VERSION 5.8 ;
BUSBITCHARS "[]" ;

UNITS
  DATABASE MICRONS 1000 ;
END UNITS

PROPERTYDEFINITIONS
  MACRO expanded_util REAL ;
END PROPERTYDEFINITIONS

LAYER OVERLAP
  TYPE OVERLAP ;
END OVERLAP

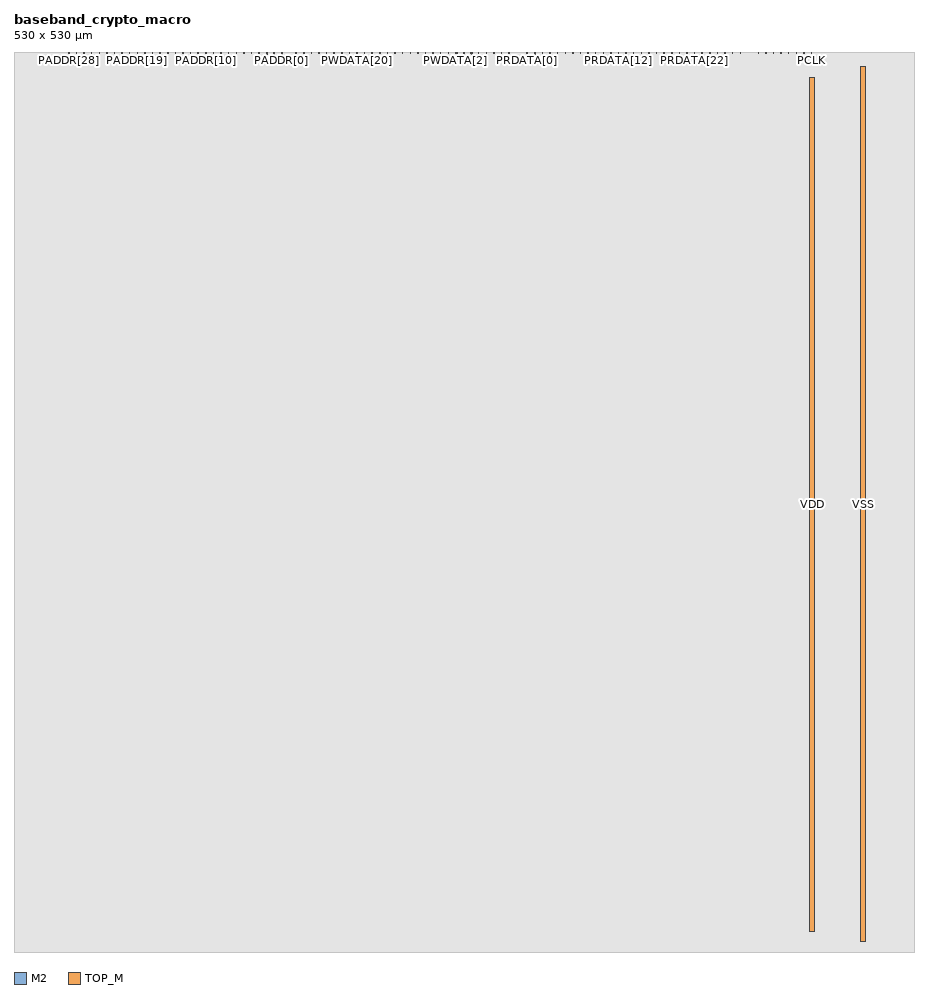
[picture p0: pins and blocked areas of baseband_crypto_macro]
MACRO baseband_crypto_macro
  CLASS BLOCK ;
  ORIGIN 0 0 ;
  SIZE 530 BY 530 ;
  SYMMETRY X Y ;
  PIN PCLK
    DIRECTION INPUT ;
    USE CLOCK ;
    PORT
      LAYER M2 ;
        RECT 469.54 529.275 469.82 530 ;
    END
  END PCLK
  PIN PRESETn
    DIRECTION INPUT ;
    USE SIGNAL ;
    PORT
      LAYER M2 ;
        RECT 465.06 529.275 465.34 530 ;
    END
  END PRESETn
  PIN PSEL
    DIRECTION INPUT ;
    USE SIGNAL ;
    PORT
      LAYER M2 ;
        RECT 460.58 529.275 460.86 530 ;
    END
  END PSEL
  PIN PENABLE
    DIRECTION INPUT ;
    USE SIGNAL ;
    PORT
      LAYER M2 ;
        RECT 456.1 529.275 456.38 530 ;
    END
  END PENABLE
  PIN PWRITE
    DIRECTION INPUT ;
    USE SIGNAL ;
    PORT
      LAYER M2 ;
        RECT 451.62 529.275 451.9 530 ;
    END
  END PWRITE
  PIN PADDR[31]
    DIRECTION INPUT ;
    USE SIGNAL ;
    PORT
      LAYER TOP_M ;
        RECT 148.58 528.72 149.02 530 ;
    END
  END PADDR[31]
  PIN PADDR[30]
    DIRECTION INPUT ;
    USE SIGNAL ;
    PORT
      LAYER TOP_M ;
        RECT 153.06 528.72 153.5 530 ;
    END
  END PADDR[30]
  PIN PADDR[29]
    DIRECTION INPUT ;
    USE SIGNAL ;
    PORT
      LAYER TOP_M ;
        RECT 157.54 528.72 157.98 530 ;
    END
  END PADDR[29]
  PIN PADDR[28]
    DIRECTION INPUT ;
    USE SIGNAL ;
    PORT
      LAYER M2 ;
        RECT 32.18 529.275 32.46 530 ;
    END
  END PADDR[28]
  PIN PADDR[27]
    DIRECTION INPUT ;
    USE SIGNAL ;
    PORT
      LAYER M2 ;
        RECT 36.66 529.275 36.94 530 ;
    END
  END PADDR[27]
  PIN PADDR[26]
    DIRECTION INPUT ;
    USE SIGNAL ;
    PORT
      LAYER M2 ;
        RECT 41.14 529.275 41.42 530 ;
    END
  END PADDR[26]
  PIN PADDR[25]
    DIRECTION INPUT ;
    USE SIGNAL ;
    PORT
      LAYER M2 ;
        RECT 45.62 529.275 45.9 530 ;
    END
  END PADDR[25]
  PIN PADDR[24]
    DIRECTION INPUT ;
    USE SIGNAL ;
    PORT
      LAYER M2 ;
        RECT 50.1 529.275 50.38 530 ;
    END
  END PADDR[24]
  PIN PADDR[23]
    DIRECTION INPUT ;
    USE SIGNAL ;
    PORT
      LAYER M2 ;
        RECT 54.58 529.275 54.86 530 ;
    END
  END PADDR[23]
  PIN PADDR[22]
    DIRECTION INPUT ;
    USE SIGNAL ;
    PORT
      LAYER M2 ;
        RECT 59.06 529.275 59.34 530 ;
    END
  END PADDR[22]
  PIN PADDR[21]
    DIRECTION INPUT ;
    USE SIGNAL ;
    PORT
      LAYER M2 ;
        RECT 63.54 529.275 63.82 530 ;
    END
  END PADDR[21]
  PIN PADDR[20]
    DIRECTION INPUT ;
    USE SIGNAL ;
    PORT
      LAYER M2 ;
        RECT 68.02 529.275 68.3 530 ;
    END
  END PADDR[20]
  PIN PADDR[19]
    DIRECTION INPUT ;
    USE SIGNAL ;
    PORT
      LAYER M2 ;
        RECT 72.5 529.275 72.78 530 ;
    END
  END PADDR[19]
  PIN PADDR[18]
    DIRECTION INPUT ;
    USE SIGNAL ;
    PORT
      LAYER M2 ;
        RECT 76.98 529.275 77.26 530 ;
    END
  END PADDR[18]
  PIN PADDR[17]
    DIRECTION INPUT ;
    USE SIGNAL ;
    PORT
      LAYER M2 ;
        RECT 81.46 529.275 81.74 530 ;
    END
  END PADDR[17]
  PIN PADDR[16]
    DIRECTION INPUT ;
    USE SIGNAL ;
    PORT
      LAYER M2 ;
        RECT 85.94 529.275 86.22 530 ;
    END
  END PADDR[16]
  PIN PADDR[15]
    DIRECTION INPUT ;
    USE SIGNAL ;
    PORT
      LAYER M2 ;
        RECT 90.42 529.275 90.7 530 ;
    END
  END PADDR[15]
  PIN PADDR[14]
    DIRECTION INPUT ;
    USE SIGNAL ;
    PORT
      LAYER M2 ;
        RECT 94.9 529.275 95.18 530 ;
    END
  END PADDR[14]
  PIN PADDR[13]
    DIRECTION INPUT ;
    USE SIGNAL ;
    PORT
      LAYER M2 ;
        RECT 99.38 529.275 99.66 530 ;
    END
  END PADDR[13]
  PIN PADDR[12]
    DIRECTION INPUT ;
    USE SIGNAL ;
    PORT
      LAYER M2 ;
        RECT 103.86 529.275 104.14 530 ;
    END
  END PADDR[12]
  PIN PADDR[11]
    DIRECTION INPUT ;
    USE SIGNAL ;
    PORT
      LAYER M2 ;
        RECT 108.34 529.275 108.62 530 ;
    END
  END PADDR[11]
  PIN PADDR[10]
    DIRECTION INPUT ;
    USE SIGNAL ;
    PORT
      LAYER M2 ;
        RECT 112.82 529.275 113.1 530 ;
    END
  END PADDR[10]
  PIN PADDR[9]
    DIRECTION INPUT ;
    USE SIGNAL ;
    PORT
      LAYER M2 ;
        RECT 117.3 529.275 117.58 530 ;
    END
  END PADDR[9]
  PIN PADDR[8]
    DIRECTION INPUT ;
    USE SIGNAL ;
    PORT
      LAYER M2 ;
        RECT 121.78 529.275 122.06 530 ;
    END
  END PADDR[8]
  PIN PADDR[7]
    DIRECTION INPUT ;
    USE SIGNAL ;
    PORT
      LAYER M2 ;
        RECT 126.26 529.275 126.54 530 ;
    END
  END PADDR[7]
  PIN PADDR[6]
    DIRECTION INPUT ;
    USE SIGNAL ;
    PORT
      LAYER M2 ;
        RECT 130.74 529.275 131.02 530 ;
    END
  END PADDR[6]
  PIN PADDR[5]
    DIRECTION INPUT ;
    USE SIGNAL ;
    PORT
      LAYER M2 ;
        RECT 135.22 529.275 135.5 530 ;
    END
  END PADDR[5]
  PIN PADDR[4]
    DIRECTION INPUT ;
    USE SIGNAL ;
    PORT
      LAYER M2 ;
        RECT 139.7 529.275 139.98 530 ;
    END
  END PADDR[4]
  PIN PADDR[3]
    DIRECTION INPUT ;
    USE SIGNAL ;
    PORT
      LAYER M2 ;
        RECT 144.18 529.275 144.46 530 ;
    END
  END PADDR[3]
  PIN PADDR[2]
    DIRECTION INPUT ;
    USE SIGNAL ;
    PORT
      LAYER M2 ;
        RECT 148.66 529.275 148.94 530 ;
    END
  END PADDR[2]
  PIN PADDR[1]
    DIRECTION INPUT ;
    USE SIGNAL ;
    PORT
      LAYER M2 ;
        RECT 153.14 529.275 153.42 530 ;
    END
  END PADDR[1]
  PIN PADDR[0]
    DIRECTION INPUT ;
    USE SIGNAL ;
    PORT
      LAYER M2 ;
        RECT 157.62 529.275 157.9 530 ;
    END
  END PADDR[0]
  PIN PWDATA[31]
    DIRECTION INPUT ;
    USE SIGNAL ;
    PORT
      LAYER TOP_M ;
        RECT 269.54 528.72 269.98 530 ;
    END
  END PWDATA[31]
  PIN PWDATA[30]
    DIRECTION INPUT ;
    USE SIGNAL ;
    PORT
      LAYER TOP_M ;
        RECT 260.58 528.72 261.02 530 ;
    END
  END PWDATA[30]
  PIN PWDATA[29]
    DIRECTION INPUT ;
    USE SIGNAL ;
    PORT
      LAYER TOP_M ;
        RECT 265.06 528.72 265.5 530 ;
    END
  END PWDATA[29]
  PIN PWDATA[28]
    DIRECTION INPUT ;
    USE SIGNAL ;
    PORT
      LAYER M2 ;
        RECT 166.02 529.275 166.3 530 ;
    END
  END PWDATA[28]
  PIN PWDATA[27]
    DIRECTION INPUT ;
    USE SIGNAL ;
    PORT
      LAYER M2 ;
        RECT 170.5 529.275 170.78 530 ;
    END
  END PWDATA[27]
  PIN PWDATA[26]
    DIRECTION INPUT ;
    USE SIGNAL ;
    PORT
      LAYER M2 ;
        RECT 174.98 529.275 175.26 530 ;
    END
  END PWDATA[26]
  PIN PWDATA[25]
    DIRECTION INPUT ;
    USE SIGNAL ;
    PORT
      LAYER M2 ;
        RECT 179.46 529.275 179.74 530 ;
    END
  END PWDATA[25]
  PIN PWDATA[24]
    DIRECTION INPUT ;
    USE SIGNAL ;
    PORT
      LAYER M2 ;
        RECT 183.94 529.275 184.22 530 ;
    END
  END PWDATA[24]
  PIN PWDATA[23]
    DIRECTION INPUT ;
    USE SIGNAL ;
    PORT
      LAYER M2 ;
        RECT 188.42 529.275 188.7 530 ;
    END
  END PWDATA[23]
  PIN PWDATA[22]
    DIRECTION INPUT ;
    USE SIGNAL ;
    PORT
      LAYER M2 ;
        RECT 192.9 529.275 193.18 530 ;
    END
  END PWDATA[22]
  PIN PWDATA[21]
    DIRECTION INPUT ;
    USE SIGNAL ;
    PORT
      LAYER M2 ;
        RECT 197.38 529.275 197.66 530 ;
    END
  END PWDATA[21]
  PIN PWDATA[20]
    DIRECTION INPUT ;
    USE SIGNAL ;
    PORT
      LAYER M2 ;
        RECT 201.86 529.275 202.14 530 ;
    END
  END PWDATA[20]
  PIN PWDATA[19]
    DIRECTION INPUT ;
    USE SIGNAL ;
    PORT
      LAYER M2 ;
        RECT 206.34 529.275 206.62 530 ;
    END
  END PWDATA[19]
  PIN PWDATA[18]
    DIRECTION INPUT ;
    USE SIGNAL ;
    PORT
      LAYER M2 ;
        RECT 210.82 529.275 211.1 530 ;
    END
  END PWDATA[18]
  PIN PWDATA[17]
    DIRECTION INPUT ;
    USE SIGNAL ;
    PORT
      LAYER M2 ;
        RECT 215.3 529.275 215.58 530 ;
    END
  END PWDATA[17]
  PIN PWDATA[16]
    DIRECTION INPUT ;
    USE SIGNAL ;
    PORT
      LAYER M2 ;
        RECT 219.78 529.275 220.06 530 ;
    END
  END PWDATA[16]
  PIN PWDATA[15]
    DIRECTION INPUT ;
    USE SIGNAL ;
    PORT
      LAYER M2 ;
        RECT 224.26 529.275 224.54 530 ;
    END
  END PWDATA[15]
  PIN PWDATA[14]
    DIRECTION INPUT ;
    USE SIGNAL ;
    PORT
      LAYER M2 ;
        RECT 228.74 529.275 229.02 530 ;
    END
  END PWDATA[14]
  PIN PWDATA[13]
    DIRECTION INPUT ;
    USE SIGNAL ;
    PORT
      LAYER M2 ;
        RECT 233.22 529.275 233.5 530 ;
    END
  END PWDATA[13]
  PIN PWDATA[12]
    DIRECTION INPUT ;
    USE SIGNAL ;
    PORT
      LAYER M2 ;
        RECT 237.7 529.275 237.98 530 ;
    END
  END PWDATA[12]
  PIN PWDATA[11]
    DIRECTION INPUT ;
    USE SIGNAL ;
    PORT
      LAYER M2 ;
        RECT 291.46 529.275 291.74 530 ;
    END
  END PWDATA[11]
  PIN PWDATA[10]
    DIRECTION INPUT ;
    USE SIGNAL ;
    PORT
      LAYER M2 ;
        RECT 242.18 529.275 242.46 530 ;
    END
  END PWDATA[10]
  PIN PWDATA[9]
    DIRECTION INPUT ;
    USE SIGNAL ;
    PORT
      LAYER M2 ;
        RECT 286.98 529.275 287.26 530 ;
    END
  END PWDATA[9]
  PIN PWDATA[8]
    DIRECTION INPUT ;
    USE SIGNAL ;
    PORT
      LAYER M2 ;
        RECT 246.66 529.275 246.94 530 ;
    END
  END PWDATA[8]
  PIN PWDATA[7]
    DIRECTION INPUT ;
    USE SIGNAL ;
    PORT
      LAYER M2 ;
        RECT 282.5 529.275 282.78 530 ;
    END
  END PWDATA[7]
  PIN PWDATA[6]
    DIRECTION INPUT ;
    USE SIGNAL ;
    PORT
      LAYER M2 ;
        RECT 251.14 529.275 251.42 530 ;
    END
  END PWDATA[6]
  PIN PWDATA[5]
    DIRECTION INPUT ;
    USE SIGNAL ;
    PORT
      LAYER M2 ;
        RECT 278.02 529.275 278.3 530 ;
    END
  END PWDATA[5]
  PIN PWDATA[4]
    DIRECTION INPUT ;
    USE SIGNAL ;
    PORT
      LAYER M2 ;
        RECT 255.62 529.275 255.9 530 ;
    END
  END PWDATA[4]
  PIN PWDATA[3]
    DIRECTION INPUT ;
    USE SIGNAL ;
    PORT
      LAYER M2 ;
        RECT 273.54 529.275 273.82 530 ;
    END
  END PWDATA[3]
  PIN PWDATA[2]
    DIRECTION INPUT ;
    USE SIGNAL ;
    PORT
      LAYER M2 ;
        RECT 260.1 529.275 260.38 530 ;
    END
  END PWDATA[2]
  PIN PWDATA[1]
    DIRECTION INPUT ;
    USE SIGNAL ;
    PORT
      LAYER M2 ;
        RECT 269.06 529.275 269.34 530 ;
    END
  END PWDATA[1]
  PIN PWDATA[0]
    DIRECTION INPUT ;
    USE SIGNAL ;
    PORT
      LAYER M2 ;
        RECT 264.58 529.275 264.86 530 ;
    END
  END PWDATA[0]
  PIN PRDATA[31]
    DIRECTION OUTPUT ;
    USE SIGNAL ;
    PORT
      LAYER TOP_M ;
        RECT 310.98 528.72 311.42 530 ;
    END
  END PRDATA[31]
  PIN PRDATA[30]
    DIRECTION OUTPUT ;
    USE SIGNAL ;
    PORT
      LAYER TOP_M ;
        RECT 306.5 528.72 306.94 530 ;
    END
  END PRDATA[30]
  PIN PRDATA[29]
    DIRECTION OUTPUT ;
    USE SIGNAL ;
    PORT
      LAYER TOP_M ;
        RECT 302.02 528.72 302.46 530 ;
    END
  END PRDATA[29]
  PIN PRDATA[28]
    DIRECTION OUTPUT ;
    USE SIGNAL ;
    PORT
      LAYER M2 ;
        RECT 427.54 529.275 427.82 530 ;
    END
  END PRDATA[28]
  PIN PRDATA[27]
    DIRECTION OUTPUT ;
    USE SIGNAL ;
    PORT
      LAYER M2 ;
        RECT 423.06 529.275 423.34 530 ;
    END
  END PRDATA[27]
  PIN PRDATA[26]
    DIRECTION OUTPUT ;
    USE SIGNAL ;
    PORT
      LAYER M2 ;
        RECT 418.58 529.275 418.86 530 ;
    END
  END PRDATA[26]
  PIN PRDATA[25]
    DIRECTION OUTPUT ;
    USE SIGNAL ;
    PORT
      LAYER M2 ;
        RECT 414.1 529.275 414.38 530 ;
    END
  END PRDATA[25]
  PIN PRDATA[24]
    DIRECTION OUTPUT ;
    USE SIGNAL ;
    PORT
      LAYER M2 ;
        RECT 409.62 529.275 409.9 530 ;
    END
  END PRDATA[24]
  PIN PRDATA[23]
    DIRECTION OUTPUT ;
    USE SIGNAL ;
    PORT
      LAYER M2 ;
        RECT 405.14 529.275 405.42 530 ;
    END
  END PRDATA[23]
  PIN PRDATA[22]
    DIRECTION OUTPUT ;
    USE SIGNAL ;
    PORT
      LAYER M2 ;
        RECT 400.66 529.275 400.94 530 ;
    END
  END PRDATA[22]
  PIN PRDATA[21]
    DIRECTION OUTPUT ;
    USE SIGNAL ;
    PORT
      LAYER M2 ;
        RECT 396.18 529.275 396.46 530 ;
    END
  END PRDATA[21]
  PIN PRDATA[20]
    DIRECTION OUTPUT ;
    USE SIGNAL ;
    PORT
      LAYER M2 ;
        RECT 391.7 529.275 391.98 530 ;
    END
  END PRDATA[20]
  PIN PRDATA[19]
    DIRECTION OUTPUT ;
    USE SIGNAL ;
    PORT
      LAYER M2 ;
        RECT 387.22 529.275 387.5 530 ;
    END
  END PRDATA[19]
  PIN PRDATA[18]
    DIRECTION OUTPUT ;
    USE SIGNAL ;
    PORT
      LAYER M2 ;
        RECT 382.74 529.275 383.02 530 ;
    END
  END PRDATA[18]
  PIN PRDATA[17]
    DIRECTION OUTPUT ;
    USE SIGNAL ;
    PORT
      LAYER M2 ;
        RECT 378.26 529.275 378.54 530 ;
    END
  END PRDATA[17]
  PIN PRDATA[16]
    DIRECTION OUTPUT ;
    USE SIGNAL ;
    PORT
      LAYER M2 ;
        RECT 373.78 529.275 374.06 530 ;
    END
  END PRDATA[16]
  PIN PRDATA[15]
    DIRECTION OUTPUT ;
    USE SIGNAL ;
    PORT
      LAYER M2 ;
        RECT 369.3 529.275 369.58 530 ;
    END
  END PRDATA[15]
  PIN PRDATA[14]
    DIRECTION OUTPUT ;
    USE SIGNAL ;
    PORT
      LAYER M2 ;
        RECT 364.82 529.275 365.1 530 ;
    END
  END PRDATA[14]
  PIN PRDATA[13]
    DIRECTION OUTPUT ;
    USE SIGNAL ;
    PORT
      LAYER M2 ;
        RECT 360.34 529.275 360.62 530 ;
    END
  END PRDATA[13]
  PIN PRDATA[12]
    DIRECTION OUTPUT ;
    USE SIGNAL ;
    PORT
      LAYER M2 ;
        RECT 355.86 529.275 356.14 530 ;
    END
  END PRDATA[12]
  PIN PRDATA[11]
    DIRECTION OUTPUT ;
    USE SIGNAL ;
    PORT
      LAYER M2 ;
        RECT 351.38 529.275 351.66 530 ;
    END
  END PRDATA[11]
  PIN PRDATA[10]
    DIRECTION OUTPUT ;
    USE SIGNAL ;
    PORT
      LAYER M2 ;
        RECT 346.9 529.275 347.18 530 ;
    END
  END PRDATA[10]
  PIN PRDATA[9]
    DIRECTION OUTPUT ;
    USE SIGNAL ;
    PORT
      LAYER M2 ;
        RECT 342.42 529.275 342.7 530 ;
    END
  END PRDATA[9]
  PIN PRDATA[8]
    DIRECTION OUTPUT ;
    USE SIGNAL ;
    PORT
      LAYER M2 ;
        RECT 337.94 529.275 338.22 530 ;
    END
  END PRDATA[8]
  PIN PRDATA[7]
    DIRECTION OUTPUT ;
    USE SIGNAL ;
    PORT
      LAYER M2 ;
        RECT 333.46 529.275 333.74 530 ;
    END
  END PRDATA[7]
  PIN PRDATA[6]
    DIRECTION OUTPUT ;
    USE SIGNAL ;
    PORT
      LAYER M2 ;
        RECT 328.98 529.275 329.26 530 ;
    END
  END PRDATA[6]
  PIN PRDATA[5]
    DIRECTION OUTPUT ;
    USE SIGNAL ;
    PORT
      LAYER M2 ;
        RECT 324.5 529.275 324.78 530 ;
    END
  END PRDATA[5]
  PIN PRDATA[4]
    DIRECTION OUTPUT ;
    USE SIGNAL ;
    PORT
      LAYER M2 ;
        RECT 320.02 529.275 320.3 530 ;
    END
  END PRDATA[4]
  PIN PRDATA[3]
    DIRECTION OUTPUT ;
    USE SIGNAL ;
    PORT
      LAYER M2 ;
        RECT 315.54 529.275 315.82 530 ;
    END
  END PRDATA[3]
  PIN PRDATA[2]
    DIRECTION OUTPUT ;
    USE SIGNAL ;
    PORT
      LAYER M2 ;
        RECT 311.06 529.275 311.34 530 ;
    END
  END PRDATA[2]
  PIN PRDATA[1]
    DIRECTION OUTPUT ;
    USE SIGNAL ;
    PORT
      LAYER M2 ;
        RECT 306.58 529.275 306.86 530 ;
    END
  END PRDATA[1]
  PIN PRDATA[0]
    DIRECTION OUTPUT ;
    USE SIGNAL ;
    PORT
      LAYER M2 ;
        RECT 302.1 529.275 302.38 530 ;
    END
  END PRDATA[0]
  PIN PREADY
    DIRECTION OUTPUT ;
    USE SIGNAL ;
    PORT
      LAYER M2 ;
        RECT 447.14 529.275 447.42 530 ;
    END
  END PREADY
  PIN rfid_rx_bit
    DIRECTION INPUT ;
    USE SIGNAL ;
    PORT
      LAYER M2 ;
        RECT 442.66 529.275 442.94 530 ;
    END
  END rfid_rx_bit
  PIN rfid_tx_bit
    DIRECTION OUTPUT ;
    USE SIGNAL ;
    PORT
      LAYER M2 ;
        RECT 438.18 529.275 438.46 530 ;
    END
  END rfid_tx_bit
  PIN VDD
    DIRECTION INPUT ;
    USE POWER ;
    PORT
      LAYER TOP_M ;
        RECT 468.75 12 471.25 515.2 ;
    END
  END VDD
  PIN VSS
    DIRECTION INPUT ;
    USE GROUND ;
    PORT
      LAYER TOP_M ;
        RECT 498.75 6 501.25 521.2 ;
    END
  END VSS
  OBS
    LAYER GC SPACING 0 ;
      RECT 0 0 530 530 ;
    LAYER M1 SPACING 0 ;
      RECT 0 0 530 530 ;
    LAYER M2 SPACING 0 ;
      RECT 264.86 529.275 269.06 530 ;
      RECT 0 0 530 529.275 ;
      RECT 396.46 529.275 400.66 530 ;
      RECT 400.94 529.275 405.14 530 ;
      RECT 405.42 529.275 409.62 530 ;
      RECT 409.9 529.275 414.1 530 ;
      RECT 414.38 529.275 418.58 530 ;
      RECT 418.86 529.275 423.06 530 ;
      RECT 423.34 529.275 427.54 530 ;
      RECT 427.82 529.275 438.18 530 ;
      RECT 438.46 529.275 442.66 530 ;
      RECT 442.94 529.275 447.14 530 ;
      RECT 447.42 529.275 451.62 530 ;
      RECT 451.9 529.275 456.1 530 ;
      RECT 456.38 529.275 460.58 530 ;
      RECT 460.86 529.275 465.06 530 ;
      RECT 465.34 529.275 469.54 530 ;
      RECT 469.82 529.275 530 530 ;
      RECT 329.26 529.275 333.46 530 ;
      RECT 333.74 529.275 337.94 530 ;
      RECT 338.22 529.275 342.42 530 ;
      RECT 342.7 529.275 346.9 530 ;
      RECT 347.18 529.275 351.38 530 ;
      RECT 351.66 529.275 355.86 530 ;
      RECT 356.14 529.275 360.34 530 ;
      RECT 360.62 529.275 364.82 530 ;
      RECT 365.1 529.275 369.3 530 ;
      RECT 369.58 529.275 373.78 530 ;
      RECT 374.06 529.275 378.26 530 ;
      RECT 378.54 529.275 382.74 530 ;
      RECT 383.02 529.275 387.22 530 ;
      RECT 387.5 529.275 391.7 530 ;
      RECT 391.98 529.275 396.18 530 ;
      RECT 269.34 529.275 273.54 530 ;
      RECT 273.82 529.275 278.02 530 ;
      RECT 278.3 529.275 282.5 530 ;
      RECT 282.78 529.275 286.98 530 ;
      RECT 287.26 529.275 291.46 530 ;
      RECT 291.74 529.275 302.1 530 ;
      RECT 302.38 529.275 306.58 530 ;
      RECT 306.86 529.275 311.06 530 ;
      RECT 311.34 529.275 315.54 530 ;
      RECT 315.82 529.275 320.02 530 ;
      RECT 320.3 529.275 324.5 530 ;
      RECT 324.78 529.275 328.98 530 ;
      RECT 131.02 529.275 135.22 530 ;
      RECT 197.66 529.275 201.86 530 ;
      RECT 202.14 529.275 206.34 530 ;
      RECT 206.62 529.275 210.82 530 ;
      RECT 211.1 529.275 215.3 530 ;
      RECT 215.58 529.275 219.78 530 ;
      RECT 220.06 529.275 224.26 530 ;
      RECT 224.54 529.275 228.74 530 ;
      RECT 229.02 529.275 233.22 530 ;
      RECT 233.5 529.275 237.7 530 ;
      RECT 237.98 529.275 242.18 530 ;
      RECT 242.46 529.275 246.66 530 ;
      RECT 246.94 529.275 251.14 530 ;
      RECT 251.42 529.275 255.62 530 ;
      RECT 255.9 529.275 260.1 530 ;
      RECT 260.38 529.275 264.58 530 ;
      RECT 135.5 529.275 139.7 530 ;
      RECT 139.98 529.275 144.18 530 ;
      RECT 144.46 529.275 148.66 530 ;
      RECT 148.94 529.275 153.14 530 ;
      RECT 153.42 529.275 157.62 530 ;
      RECT 157.9 529.275 166.02 530 ;
      RECT 166.3 529.275 170.5 530 ;
      RECT 170.78 529.275 174.98 530 ;
      RECT 175.26 529.275 179.46 530 ;
      RECT 179.74 529.275 183.94 530 ;
      RECT 184.22 529.275 188.42 530 ;
      RECT 188.7 529.275 192.9 530 ;
      RECT 193.18 529.275 197.38 530 ;
      RECT 63.82 529.275 68.02 530 ;
      RECT 68.3 529.275 72.5 530 ;
      RECT 72.78 529.275 76.98 530 ;
      RECT 77.26 529.275 81.46 530 ;
      RECT 81.74 529.275 85.94 530 ;
      RECT 86.22 529.275 90.42 530 ;
      RECT 90.7 529.275 94.9 530 ;
      RECT 95.18 529.275 99.38 530 ;
      RECT 99.66 529.275 103.86 530 ;
      RECT 104.14 529.275 108.34 530 ;
      RECT 108.62 529.275 112.82 530 ;
      RECT 113.1 529.275 117.3 530 ;
      RECT 117.58 529.275 121.78 530 ;
      RECT 122.06 529.275 126.26 530 ;
      RECT 126.54 529.275 130.74 530 ;
      RECT 0 529.275 32.18 530 ;
      RECT 32.46 529.275 36.66 530 ;
      RECT 36.94 529.275 41.14 530 ;
      RECT 41.42 529.275 45.62 530 ;
      RECT 45.9 529.275 50.1 530 ;
      RECT 50.38 529.275 54.58 530 ;
      RECT 54.86 529.275 59.06 530 ;
      RECT 59.34 529.275 63.54 530 ;
    LAYER M3 SPACING 0 ;
      RECT 0 0 530 530 ;
    LAYER TOP_M SPACING 0 ;
      RECT 0 528.72 148.58 530 ;
      RECT 149.02 528.72 153.06 530 ;
      RECT 153.5 528.72 157.54 530 ;
      RECT 157.98 528.72 260.58 530 ;
      RECT 261.02 528.72 265.06 530 ;
      RECT 265.5 528.72 269.54 530 ;
      RECT 269.98 528.72 302.02 530 ;
      RECT 302.46 528.72 306.5 530 ;
      RECT 306.94 528.72 310.98 530 ;
      RECT 311.42 528.72 530 530 ;
      RECT 0 521.2 530 528.72 ;
      RECT 0 515.2 498.75 521.2 ;
      RECT 0 12 468.75 515.2 ;
      RECT 471.25 12 498.75 515.2 ;
      RECT 501.25 6 530 521.2 ;
      RECT 0 6 498.75 12 ;
      RECT 0 0 530 6 ;
    LAYER WN SPACING 0 ;
      RECT 0 0 530 530 ;
    LAYER XP SPACING 0 ;
      RECT 0 0 530 530 ;
    LAYER XN SPACING 0 ;
      RECT 0 0 530 530 ;
    LAYER M2 ;
      RECT 0.28 0.28 529.72 528.995 ;
      RECT 396.74 528.995 400.38 529.72 ;
      RECT 401.22 528.995 404.86 529.72 ;
      RECT 405.7 528.995 409.34 529.72 ;
      RECT 410.18 528.995 413.82 529.72 ;
      RECT 414.66 528.995 418.3 529.72 ;
      RECT 419.14 528.995 422.78 529.72 ;
      RECT 423.62 528.995 427.26 529.72 ;
      RECT 428.1 528.995 437.9 529.72 ;
      RECT 438.74 528.995 442.38 529.72 ;
      RECT 443.22 528.995 446.86 529.72 ;
      RECT 447.7 528.995 451.34 529.72 ;
      RECT 452.18 528.995 455.82 529.72 ;
      RECT 456.66 528.995 460.3 529.72 ;
      RECT 461.14 528.995 464.78 529.72 ;
      RECT 465.62 528.995 469.26 529.72 ;
      RECT 470.1 528.995 529.72 529.72 ;
      RECT 329.54 528.995 333.18 529.72 ;
      RECT 334.02 528.995 337.66 529.72 ;
      RECT 338.5 528.995 342.14 529.72 ;
      RECT 342.98 528.995 346.62 529.72 ;
      RECT 347.46 528.995 351.1 529.72 ;
      RECT 351.94 528.995 355.58 529.72 ;
      RECT 356.42 528.995 360.06 529.72 ;
      RECT 360.9 528.995 364.54 529.72 ;
      RECT 365.38 528.995 369.02 529.72 ;
      RECT 369.86 528.995 373.5 529.72 ;
      RECT 374.34 528.995 377.98 529.72 ;
      RECT 378.82 528.995 382.46 529.72 ;
      RECT 383.3 528.995 386.94 529.72 ;
      RECT 387.78 528.995 391.42 529.72 ;
      RECT 392.26 528.995 395.9 529.72 ;
      RECT 265.14 528.995 268.78 529.72 ;
      RECT 269.62 528.995 273.26 529.72 ;
      RECT 274.1 528.995 277.74 529.72 ;
      RECT 278.58 528.995 282.22 529.72 ;
      RECT 283.06 528.995 286.7 529.72 ;
      RECT 287.54 528.995 291.18 529.72 ;
      RECT 292.02 528.995 301.82 529.72 ;
      RECT 302.66 528.995 306.3 529.72 ;
      RECT 307.14 528.995 310.78 529.72 ;
      RECT 311.62 528.995 315.26 529.72 ;
      RECT 316.1 528.995 319.74 529.72 ;
      RECT 320.58 528.995 324.22 529.72 ;
      RECT 325.06 528.995 328.7 529.72 ;
      RECT 131.3 528.995 134.94 529.72 ;
      RECT 197.94 528.995 201.58 529.72 ;
      RECT 202.42 528.995 206.06 529.72 ;
      RECT 206.9 528.995 210.54 529.72 ;
      RECT 211.38 528.995 215.02 529.72 ;
      RECT 215.86 528.995 219.5 529.72 ;
      RECT 220.34 528.995 223.98 529.72 ;
      RECT 224.82 528.995 228.46 529.72 ;
      RECT 229.3 528.995 232.94 529.72 ;
      RECT 233.78 528.995 237.42 529.72 ;
      RECT 238.26 528.995 241.9 529.72 ;
      RECT 242.74 528.995 246.38 529.72 ;
      RECT 247.22 528.995 250.86 529.72 ;
      RECT 251.7 528.995 255.34 529.72 ;
      RECT 256.18 528.995 259.82 529.72 ;
      RECT 260.66 528.995 264.3 529.72 ;
      RECT 135.78 528.995 139.42 529.72 ;
      RECT 140.26 528.995 143.9 529.72 ;
      RECT 144.74 528.995 148.38 529.72 ;
      RECT 149.22 528.995 152.86 529.72 ;
      RECT 153.7 528.995 157.34 529.72 ;
      RECT 158.18 528.995 165.74 529.72 ;
      RECT 166.58 528.995 170.22 529.72 ;
      RECT 171.06 528.995 174.7 529.72 ;
      RECT 175.54 528.995 179.18 529.72 ;
      RECT 180.02 528.995 183.66 529.72 ;
      RECT 184.5 528.995 188.14 529.72 ;
      RECT 188.98 528.995 192.62 529.72 ;
      RECT 193.46 528.995 197.1 529.72 ;
      RECT 64.1 528.995 67.74 529.72 ;
      RECT 68.58 528.995 72.22 529.72 ;
      RECT 73.06 528.995 76.7 529.72 ;
      RECT 77.54 528.995 81.18 529.72 ;
      RECT 82.02 528.995 85.66 529.72 ;
      RECT 86.5 528.995 90.14 529.72 ;
      RECT 90.98 528.995 94.62 529.72 ;
      RECT 95.46 528.995 99.1 529.72 ;
      RECT 99.94 528.995 103.58 529.72 ;
      RECT 104.42 528.995 108.06 529.72 ;
      RECT 108.9 528.995 112.54 529.72 ;
      RECT 113.38 528.995 117.02 529.72 ;
      RECT 117.86 528.995 121.5 529.72 ;
      RECT 122.34 528.995 125.98 529.72 ;
      RECT 126.82 528.995 130.46 529.72 ;
      RECT 0.28 528.995 31.9 529.72 ;
      RECT 32.74 528.995 36.38 529.72 ;
      RECT 37.22 528.995 40.86 529.72 ;
      RECT 41.7 528.995 45.34 529.72 ;
      RECT 46.18 528.995 49.82 529.72 ;
      RECT 50.66 528.995 54.3 529.72 ;
      RECT 55.14 528.995 58.78 529.72 ;
      RECT 59.62 528.995 63.26 529.72 ;
    LAYER TOP_M ;
      RECT 0.46 528.26 148.12 529.54 ;
      RECT 149.48 528.26 152.6 529.54 ;
      RECT 153.96 528.26 157.08 529.54 ;
      RECT 158.44 528.26 260.12 529.54 ;
      RECT 261.48 528.26 264.6 529.54 ;
      RECT 265.96 528.26 269.08 529.54 ;
      RECT 270.44 528.26 301.56 529.54 ;
      RECT 302.92 528.26 306.04 529.54 ;
      RECT 307.4 528.26 310.52 529.54 ;
      RECT 311.88 528.26 529.54 529.54 ;
      RECT 0.46 521.66 529.54 528.26 ;
      RECT 0.46 515.66 498.29 521.66 ;
      RECT 0.46 11.54 468.29 515.66 ;
      RECT 471.71 11.54 498.29 515.66 ;
      RECT 501.71 5.54 529.54 521.66 ;
      RECT 0.46 5.54 498.29 11.54 ;
      RECT 0.46 0.46 529.54 5.54 ;
    LAYER M1 ;
      RECT 0.23 0.23 529.77 529.77 ;
    LAYER M3 ;
      RECT 0.28 0.28 529.72 529.72 ;
    LAYER WN ;
      RECT 1.4 1.4 528.6 528.6 ;
    LAYER GC ;
      RECT 0.25 0.25 529.75 529.75 ;
    LAYER XP ;
      RECT 0.44 0.44 529.56 529.56 ;
    LAYER XN ;
      RECT 0.44 0.44 529.56 529.56 ;
    LAYER V3 ;
      RECT 442.67 529.22 442.93 529.48 ;
      RECT 269.07 529.13 269.33 529.39 ;
      RECT 130.75 529.13 131.01 529.39 ;
    LAYER TOP_V ;
      RECT 269.94 529.17 270.3 529.53 ;
      RECT 260.62 529.17 260.98 529.53 ;
      RECT 265.1 528.56 265.46 528.92 ;
      RECT 500.53 520.44 500.89 520.8 ;
      RECT 499.82 520.44 500.18 520.8 ;
      RECT 499.11 520.44 499.47 520.8 ;
      RECT 500.53 519.73 500.89 520.09 ;
      RECT 499.82 519.73 500.18 520.09 ;
      RECT 499.11 519.73 499.47 520.09 ;
      RECT 500.53 519.02 500.89 519.38 ;
      RECT 499.82 519.02 500.18 519.38 ;
      RECT 499.11 519.02 499.47 519.38 ;
      RECT 500.53 518.31 500.89 518.67 ;
      RECT 499.82 518.31 500.18 518.67 ;
      RECT 499.11 518.31 499.47 518.67 ;
      RECT 500.53 517.6 500.89 517.96 ;
      RECT 499.82 517.6 500.18 517.96 ;
      RECT 499.11 517.6 499.47 517.96 ;
      RECT 470.53 514.44 470.89 514.8 ;
      RECT 469.82 514.44 470.18 514.8 ;
      RECT 469.11 514.44 469.47 514.8 ;
      RECT 470.53 513.73 470.89 514.09 ;
      RECT 469.82 513.73 470.18 514.09 ;
      RECT 469.11 513.73 469.47 514.09 ;
      RECT 470.53 513.02 470.89 513.38 ;
      RECT 469.82 513.02 470.18 513.38 ;
      RECT 469.11 513.02 469.47 513.38 ;
      RECT 470.53 512.31 470.89 512.67 ;
      RECT 469.82 512.31 470.18 512.67 ;
      RECT 469.11 512.31 469.47 512.67 ;
      RECT 470.53 511.6 470.89 511.96 ;
      RECT 469.82 511.6 470.18 511.96 ;
      RECT 469.11 511.6 469.47 511.96 ;
      RECT 500.53 507.02 500.89 507.38 ;
      RECT 499.82 507.02 500.18 507.38 ;
      RECT 499.11 507.02 499.47 507.38 ;
      RECT 470.53 501.42 470.89 501.78 ;
      RECT 469.82 501.42 470.18 501.78 ;
      RECT 469.11 501.42 469.47 501.78 ;
      RECT 500.53 495.82 500.89 496.18 ;
      RECT 499.82 495.82 500.18 496.18 ;
      RECT 499.11 495.82 499.47 496.18 ;
      RECT 470.53 490.22 470.89 490.58 ;
      RECT 469.82 490.22 470.18 490.58 ;
      RECT 469.11 490.22 469.47 490.58 ;
      RECT 500.53 484.62 500.89 484.98 ;
      RECT 499.82 484.62 500.18 484.98 ;
      RECT 499.11 484.62 499.47 484.98 ;
      RECT 470.53 479.375 470.89 479.735 ;
      RECT 469.82 479.375 470.18 479.735 ;
      RECT 469.11 479.375 469.47 479.735 ;
      RECT 470.53 478.665 470.89 479.025 ;
      RECT 469.82 478.665 470.18 479.025 ;
      RECT 469.11 478.665 469.47 479.025 ;
      RECT 500.53 473.42 500.89 473.78 ;
      RECT 499.82 473.42 500.18 473.78 ;
      RECT 499.11 473.42 499.47 473.78 ;
      RECT 470.53 467.82 470.89 468.18 ;
      RECT 469.82 467.82 470.18 468.18 ;
      RECT 469.11 467.82 469.47 468.18 ;
      RECT 500.53 462.22 500.89 462.58 ;
      RECT 499.82 462.22 500.18 462.58 ;
      RECT 499.11 462.22 499.47 462.58 ;
      RECT 470.53 456.62 470.89 456.98 ;
      RECT 469.82 456.62 470.18 456.98 ;
      RECT 469.11 456.62 469.47 456.98 ;
      RECT 500.53 451.375 500.89 451.735 ;
      RECT 499.82 451.375 500.18 451.735 ;
      RECT 499.11 451.375 499.47 451.735 ;
      RECT 500.53 450.665 500.89 451.025 ;
      RECT 499.82 450.665 500.18 451.025 ;
      RECT 499.11 450.665 499.47 451.025 ;
      RECT 470.53 445.42 470.89 445.78 ;
      RECT 469.82 445.42 470.18 445.78 ;
      RECT 469.11 445.42 469.47 445.78 ;
      RECT 500.53 439.82 500.89 440.18 ;
      RECT 499.82 439.82 500.18 440.18 ;
      RECT 499.11 439.82 499.47 440.18 ;
      RECT 470.53 434.22 470.89 434.58 ;
      RECT 469.82 434.22 470.18 434.58 ;
      RECT 469.11 434.22 469.47 434.58 ;
      RECT 500.53 428.62 500.89 428.98 ;
      RECT 499.82 428.62 500.18 428.98 ;
      RECT 499.11 428.62 499.47 428.98 ;
      RECT 470.53 423.375 470.89 423.735 ;
      RECT 469.82 423.375 470.18 423.735 ;
      RECT 469.11 423.375 469.47 423.735 ;
      RECT 470.53 422.665 470.89 423.025 ;
      RECT 469.82 422.665 470.18 423.025 ;
      RECT 469.11 422.665 469.47 423.025 ;
      RECT 500.53 417.42 500.89 417.78 ;
      RECT 499.82 417.42 500.18 417.78 ;
      RECT 499.11 417.42 499.47 417.78 ;
      RECT 470.53 411.82 470.89 412.18 ;
      RECT 469.82 411.82 470.18 412.18 ;
      RECT 469.11 411.82 469.47 412.18 ;
      RECT 500.53 406.22 500.89 406.58 ;
      RECT 499.82 406.22 500.18 406.58 ;
      RECT 499.11 406.22 499.47 406.58 ;
      RECT 470.53 400.62 470.89 400.98 ;
      RECT 469.82 400.62 470.18 400.98 ;
      RECT 469.11 400.62 469.47 400.98 ;
      RECT 500.53 395.375 500.89 395.735 ;
      RECT 499.82 395.375 500.18 395.735 ;
      RECT 499.11 395.375 499.47 395.735 ;
      RECT 500.53 394.665 500.89 395.025 ;
      RECT 499.82 394.665 500.18 395.025 ;
      RECT 499.11 394.665 499.47 395.025 ;
      RECT 470.53 389.42 470.89 389.78 ;
      RECT 469.82 389.42 470.18 389.78 ;
      RECT 469.11 389.42 469.47 389.78 ;
      RECT 500.53 383.82 500.89 384.18 ;
      RECT 499.82 383.82 500.18 384.18 ;
      RECT 499.11 383.82 499.47 384.18 ;
      RECT 470.53 378.22 470.89 378.58 ;
      RECT 469.82 378.22 470.18 378.58 ;
      RECT 469.11 378.22 469.47 378.58 ;
      RECT 500.53 372.62 500.89 372.98 ;
      RECT 499.82 372.62 500.18 372.98 ;
      RECT 499.11 372.62 499.47 372.98 ;
      RECT 470.53 367.375 470.89 367.735 ;
      RECT 469.82 367.375 470.18 367.735 ;
      RECT 469.11 367.375 469.47 367.735 ;
      RECT 470.53 366.665 470.89 367.025 ;
      RECT 469.82 366.665 470.18 367.025 ;
      RECT 469.11 366.665 469.47 367.025 ;
      RECT 500.53 361.42 500.89 361.78 ;
      RECT 499.82 361.42 500.18 361.78 ;
      RECT 499.11 361.42 499.47 361.78 ;
      RECT 470.53 355.82 470.89 356.18 ;
      RECT 469.82 355.82 470.18 356.18 ;
      RECT 469.11 355.82 469.47 356.18 ;
      RECT 500.53 350.22 500.89 350.58 ;
      RECT 499.82 350.22 500.18 350.58 ;
      RECT 499.11 350.22 499.47 350.58 ;
      RECT 470.53 344.62 470.89 344.98 ;
      RECT 469.82 344.62 470.18 344.98 ;
      RECT 469.11 344.62 469.47 344.98 ;
      RECT 500.53 339.375 500.89 339.735 ;
      RECT 499.82 339.375 500.18 339.735 ;
      RECT 499.11 339.375 499.47 339.735 ;
      RECT 500.53 338.665 500.89 339.025 ;
      RECT 499.82 338.665 500.18 339.025 ;
      RECT 499.11 338.665 499.47 339.025 ;
      RECT 470.53 333.42 470.89 333.78 ;
      RECT 469.82 333.42 470.18 333.78 ;
      RECT 469.11 333.42 469.47 333.78 ;
      RECT 500.53 327.82 500.89 328.18 ;
      RECT 499.82 327.82 500.18 328.18 ;
      RECT 499.11 327.82 499.47 328.18 ;
      RECT 470.53 322.22 470.89 322.58 ;
      RECT 469.82 322.22 470.18 322.58 ;
      RECT 469.11 322.22 469.47 322.58 ;
      RECT 500.53 316.62 500.89 316.98 ;
      RECT 499.82 316.62 500.18 316.98 ;
      RECT 499.11 316.62 499.47 316.98 ;
      RECT 470.53 311.375 470.89 311.735 ;
      RECT 469.82 311.375 470.18 311.735 ;
      RECT 469.11 311.375 469.47 311.735 ;
      RECT 470.53 310.665 470.89 311.025 ;
      RECT 469.82 310.665 470.18 311.025 ;
      RECT 469.11 310.665 469.47 311.025 ;
      RECT 500.53 305.42 500.89 305.78 ;
      RECT 499.82 305.42 500.18 305.78 ;
      RECT 499.11 305.42 499.47 305.78 ;
      RECT 470.53 299.82 470.89 300.18 ;
      RECT 469.82 299.82 470.18 300.18 ;
      RECT 469.11 299.82 469.47 300.18 ;
      RECT 500.53 294.22 500.89 294.58 ;
      RECT 499.82 294.22 500.18 294.58 ;
      RECT 499.11 294.22 499.47 294.58 ;
      RECT 470.53 288.62 470.89 288.98 ;
      RECT 469.82 288.62 470.18 288.98 ;
      RECT 469.11 288.62 469.47 288.98 ;
      RECT 500.53 283.375 500.89 283.735 ;
      RECT 499.82 283.375 500.18 283.735 ;
      RECT 499.11 283.375 499.47 283.735 ;
      RECT 500.53 282.665 500.89 283.025 ;
      RECT 499.82 282.665 500.18 283.025 ;
      RECT 499.11 282.665 499.47 283.025 ;
      RECT 470.53 277.42 470.89 277.78 ;
      RECT 469.82 277.42 470.18 277.78 ;
      RECT 469.11 277.42 469.47 277.78 ;
      RECT 500.53 271.82 500.89 272.18 ;
      RECT 499.82 271.82 500.18 272.18 ;
      RECT 499.11 271.82 499.47 272.18 ;
      RECT 470.53 266.22 470.89 266.58 ;
      RECT 469.82 266.22 470.18 266.58 ;
      RECT 469.11 266.22 469.47 266.58 ;
      RECT 500.53 260.62 500.89 260.98 ;
      RECT 499.82 260.62 500.18 260.98 ;
      RECT 499.11 260.62 499.47 260.98 ;
      RECT 470.53 255.375 470.89 255.735 ;
      RECT 469.82 255.375 470.18 255.735 ;
      RECT 469.11 255.375 469.47 255.735 ;
      RECT 470.53 254.665 470.89 255.025 ;
      RECT 469.82 254.665 470.18 255.025 ;
      RECT 469.11 254.665 469.47 255.025 ;
      RECT 500.53 249.42 500.89 249.78 ;
      RECT 499.82 249.42 500.18 249.78 ;
      RECT 499.11 249.42 499.47 249.78 ;
      RECT 470.53 243.82 470.89 244.18 ;
      RECT 469.82 243.82 470.18 244.18 ;
      RECT 469.11 243.82 469.47 244.18 ;
      RECT 500.53 238.22 500.89 238.58 ;
      RECT 499.82 238.22 500.18 238.58 ;
      RECT 499.11 238.22 499.47 238.58 ;
      RECT 470.53 232.62 470.89 232.98 ;
      RECT 469.82 232.62 470.18 232.98 ;
      RECT 469.11 232.62 469.47 232.98 ;
      RECT 500.53 227.375 500.89 227.735 ;
      RECT 499.82 227.375 500.18 227.735 ;
      RECT 499.11 227.375 499.47 227.735 ;
      RECT 500.53 226.665 500.89 227.025 ;
      RECT 499.82 226.665 500.18 227.025 ;
      RECT 499.11 226.665 499.47 227.025 ;
      RECT 470.53 221.42 470.89 221.78 ;
      RECT 469.82 221.42 470.18 221.78 ;
      RECT 469.11 221.42 469.47 221.78 ;
      RECT 500.53 215.82 500.89 216.18 ;
      RECT 499.82 215.82 500.18 216.18 ;
      RECT 499.11 215.82 499.47 216.18 ;
      RECT 470.53 210.22 470.89 210.58 ;
      RECT 469.82 210.22 470.18 210.58 ;
      RECT 469.11 210.22 469.47 210.58 ;
      RECT 500.53 204.62 500.89 204.98 ;
      RECT 499.82 204.62 500.18 204.98 ;
      RECT 499.11 204.62 499.47 204.98 ;
      RECT 470.53 199.375 470.89 199.735 ;
      RECT 469.82 199.375 470.18 199.735 ;
      RECT 469.11 199.375 469.47 199.735 ;
      RECT 470.53 198.665 470.89 199.025 ;
      RECT 469.82 198.665 470.18 199.025 ;
      RECT 469.11 198.665 469.47 199.025 ;
      RECT 500.53 193.42 500.89 193.78 ;
      RECT 499.82 193.42 500.18 193.78 ;
      RECT 499.11 193.42 499.47 193.78 ;
      RECT 470.53 187.82 470.89 188.18 ;
      RECT 469.82 187.82 470.18 188.18 ;
      RECT 469.11 187.82 469.47 188.18 ;
      RECT 500.53 182.22 500.89 182.58 ;
      RECT 499.82 182.22 500.18 182.58 ;
      RECT 499.11 182.22 499.47 182.58 ;
      RECT 470.53 176.62 470.89 176.98 ;
      RECT 469.82 176.62 470.18 176.98 ;
      RECT 469.11 176.62 469.47 176.98 ;
      RECT 500.53 171.375 500.89 171.735 ;
      RECT 499.82 171.375 500.18 171.735 ;
      RECT 499.11 171.375 499.47 171.735 ;
      RECT 500.53 170.665 500.89 171.025 ;
      RECT 499.82 170.665 500.18 171.025 ;
      RECT 499.11 170.665 499.47 171.025 ;
      RECT 470.53 165.42 470.89 165.78 ;
      RECT 469.82 165.42 470.18 165.78 ;
      RECT 469.11 165.42 469.47 165.78 ;
      RECT 500.53 159.82 500.89 160.18 ;
      RECT 499.82 159.82 500.18 160.18 ;
      RECT 499.11 159.82 499.47 160.18 ;
      RECT 470.53 154.22 470.89 154.58 ;
      RECT 469.82 154.22 470.18 154.58 ;
      RECT 469.11 154.22 469.47 154.58 ;
      RECT 500.53 148.62 500.89 148.98 ;
      RECT 499.82 148.62 500.18 148.98 ;
      RECT 499.11 148.62 499.47 148.98 ;
      RECT 470.53 143.375 470.89 143.735 ;
      RECT 469.82 143.375 470.18 143.735 ;
      RECT 469.11 143.375 469.47 143.735 ;
      RECT 470.53 142.665 470.89 143.025 ;
      RECT 469.82 142.665 470.18 143.025 ;
      RECT 469.11 142.665 469.47 143.025 ;
      RECT 500.53 137.42 500.89 137.78 ;
      RECT 499.82 137.42 500.18 137.78 ;
      RECT 499.11 137.42 499.47 137.78 ;
      RECT 470.53 131.82 470.89 132.18 ;
      RECT 469.82 131.82 470.18 132.18 ;
      RECT 469.11 131.82 469.47 132.18 ;
      RECT 500.53 126.22 500.89 126.58 ;
      RECT 499.82 126.22 500.18 126.58 ;
      RECT 499.11 126.22 499.47 126.58 ;
      RECT 470.53 120.62 470.89 120.98 ;
      RECT 469.82 120.62 470.18 120.98 ;
      RECT 469.11 120.62 469.47 120.98 ;
      RECT 500.53 115.375 500.89 115.735 ;
      RECT 499.82 115.375 500.18 115.735 ;
      RECT 499.11 115.375 499.47 115.735 ;
      RECT 500.53 114.665 500.89 115.025 ;
      RECT 499.82 114.665 500.18 115.025 ;
      RECT 499.11 114.665 499.47 115.025 ;
      RECT 470.53 109.42 470.89 109.78 ;
      RECT 469.82 109.42 470.18 109.78 ;
      RECT 469.11 109.42 469.47 109.78 ;
      RECT 500.53 103.82 500.89 104.18 ;
      RECT 499.82 103.82 500.18 104.18 ;
      RECT 499.11 103.82 499.47 104.18 ;
      RECT 470.53 98.22 470.89 98.58 ;
      RECT 469.82 98.22 470.18 98.58 ;
      RECT 469.11 98.22 469.47 98.58 ;
      RECT 500.53 92.62 500.89 92.98 ;
      RECT 499.82 92.62 500.18 92.98 ;
      RECT 499.11 92.62 499.47 92.98 ;
      RECT 470.53 87.375 470.89 87.735 ;
      RECT 469.82 87.375 470.18 87.735 ;
      RECT 469.11 87.375 469.47 87.735 ;
      RECT 470.53 86.665 470.89 87.025 ;
      RECT 469.82 86.665 470.18 87.025 ;
      RECT 469.11 86.665 469.47 87.025 ;
      RECT 500.53 81.42 500.89 81.78 ;
      RECT 499.82 81.42 500.18 81.78 ;
      RECT 499.11 81.42 499.47 81.78 ;
      RECT 470.53 75.82 470.89 76.18 ;
      RECT 469.82 75.82 470.18 76.18 ;
      RECT 469.11 75.82 469.47 76.18 ;
      RECT 500.53 70.22 500.89 70.58 ;
      RECT 499.82 70.22 500.18 70.58 ;
      RECT 499.11 70.22 499.47 70.58 ;
      RECT 470.53 64.62 470.89 64.98 ;
      RECT 469.82 64.62 470.18 64.98 ;
      RECT 469.11 64.62 469.47 64.98 ;
      RECT 500.53 59.375 500.89 59.735 ;
      RECT 499.82 59.375 500.18 59.735 ;
      RECT 499.11 59.375 499.47 59.735 ;
      RECT 500.53 58.665 500.89 59.025 ;
      RECT 499.82 58.665 500.18 59.025 ;
      RECT 499.11 58.665 499.47 59.025 ;
      RECT 470.53 53.42 470.89 53.78 ;
      RECT 469.82 53.42 470.18 53.78 ;
      RECT 469.11 53.42 469.47 53.78 ;
      RECT 500.53 47.82 500.89 48.18 ;
      RECT 499.82 47.82 500.18 48.18 ;
      RECT 499.11 47.82 499.47 48.18 ;
      RECT 470.53 42.22 470.89 42.58 ;
      RECT 469.82 42.22 470.18 42.58 ;
      RECT 469.11 42.22 469.47 42.58 ;
      RECT 500.53 36.62 500.89 36.98 ;
      RECT 499.82 36.62 500.18 36.98 ;
      RECT 499.11 36.62 499.47 36.98 ;
      RECT 470.53 31.375 470.89 31.735 ;
      RECT 469.82 31.375 470.18 31.735 ;
      RECT 469.11 31.375 469.47 31.735 ;
      RECT 470.53 30.665 470.89 31.025 ;
      RECT 469.82 30.665 470.18 31.025 ;
      RECT 469.11 30.665 469.47 31.025 ;
      RECT 500.53 25.42 500.89 25.78 ;
      RECT 499.82 25.42 500.18 25.78 ;
      RECT 499.11 25.42 499.47 25.78 ;
      RECT 470.53 19.82 470.89 20.18 ;
      RECT 469.82 19.82 470.18 20.18 ;
      RECT 469.11 19.82 469.47 20.18 ;
      RECT 470.53 15.24 470.89 15.6 ;
      RECT 469.82 15.24 470.18 15.6 ;
      RECT 469.11 15.24 469.47 15.6 ;
      RECT 470.53 14.53 470.89 14.89 ;
      RECT 469.82 14.53 470.18 14.89 ;
      RECT 469.11 14.53 469.47 14.89 ;
      RECT 470.53 13.82 470.89 14.18 ;
      RECT 469.82 13.82 470.18 14.18 ;
      RECT 469.11 13.82 469.47 14.18 ;
      RECT 470.53 13.11 470.89 13.47 ;
      RECT 469.82 13.11 470.18 13.47 ;
      RECT 469.11 13.11 469.47 13.47 ;
      RECT 470.53 12.4 470.89 12.76 ;
      RECT 469.82 12.4 470.18 12.76 ;
      RECT 469.11 12.4 469.47 12.76 ;
      RECT 500.53 9.24 500.89 9.6 ;
      RECT 499.82 9.24 500.18 9.6 ;
      RECT 499.11 9.24 499.47 9.6 ;
      RECT 500.53 8.53 500.89 8.89 ;
      RECT 499.82 8.53 500.18 8.89 ;
      RECT 499.11 8.53 499.47 8.89 ;
      RECT 500.53 7.82 500.89 8.18 ;
      RECT 499.82 7.82 500.18 8.18 ;
      RECT 499.11 7.82 499.47 8.18 ;
      RECT 500.53 7.11 500.89 7.47 ;
      RECT 499.82 7.11 500.18 7.47 ;
      RECT 499.11 7.11 499.47 7.47 ;
      RECT 500.53 6.4 500.89 6.76 ;
      RECT 499.82 6.4 500.18 6.76 ;
      RECT 499.11 6.4 499.47 6.76 ;
    LAYER OVERLAP ;
      RECT 0 0 530 530 ;
  END
  PROPERTY expanded_util 0.67 ;
END baseband_crypto_macro

END LIBRARY
